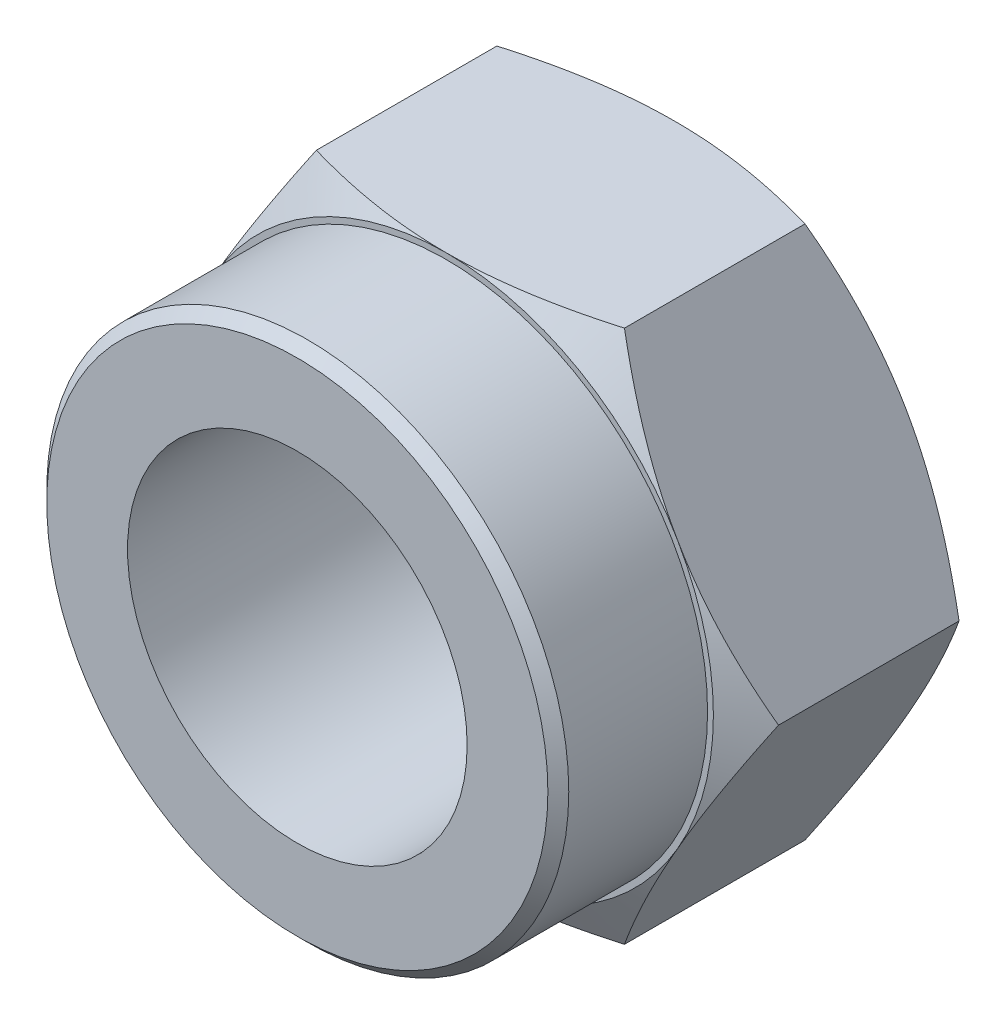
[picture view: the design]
ISO-10303-21;
HEADER;
FILE_DESCRIPTION(('STEP AP214'),'2;1');
FILE_NAME('part.step','',(''),(''),'','','');
FILE_SCHEMA(('AUTOMOTIVE_DESIGN { 1 0 10303 214 1 1 1 1 }'));
ENDSEC;
DATA;
#1=APPLICATION_CONTEXT('core data for automotive mechanical design processes');
#2=APPLICATION_PROTOCOL_DEFINITION('international standard','automotive_design',2000,#1);
#3=PRODUCT_CONTEXT('',#1,'mechanical');
#4=PRODUCT('Part','Part','',(#3));
#5=PRODUCT_RELATED_PRODUCT_CATEGORY('part','',(#4));
#6=PRODUCT_DEFINITION_FORMATION('','',#4);
#7=PRODUCT_DEFINITION_CONTEXT('part definition',#1,'design');
#8=PRODUCT_DEFINITION('design','',#6,#7);
#9=PRODUCT_DEFINITION_SHAPE('','',#8);
#10=(LENGTH_UNIT() NAMED_UNIT(*) SI_UNIT(.MILLI.,.METRE.));
#11=(NAMED_UNIT(*) PLANE_ANGLE_UNIT() SI_UNIT($,.RADIAN.));
#12=(NAMED_UNIT(*) SI_UNIT($,.STERADIAN.) SOLID_ANGLE_UNIT());
#13=UNCERTAINTY_MEASURE_WITH_UNIT(LENGTH_MEASURE(1.E-05),#10,'distance_accuracy_value','');
#14=(GEOMETRIC_REPRESENTATION_CONTEXT(3) GLOBAL_UNCERTAINTY_ASSIGNED_CONTEXT((#13)) GLOBAL_UNIT_ASSIGNED_CONTEXT((#10,
#11,#12)) REPRESENTATION_CONTEXT('',''));
#15=CARTESIAN_POINT('',(0.,0.,0.));
#16=DIRECTION('',(0.,0.,1.));
#17=DIRECTION('',(1.,0.,0.));
#18=AXIS2_PLACEMENT_3D('',#15,#16,#17);
#19=CARTESIAN_POINT('',(47.6313972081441,-27.5,-23.52));
#20=DIRECTION('',(0.,0.,1.));
#21=DIRECTION('',(1.,0.,0.));
#22=AXIS2_PLACEMENT_3D('',#19,#20,#21);
#23=PLANE('',#22);
#24=CARTESIAN_POINT('',(0.,0.,-23.52));
#25=DIRECTION('',(0.,0.,1.));
#26=DIRECTION('',(1.,0.,0.));
#27=AXIS2_PLACEMENT_3D('',#24,#25,#26);
#28=CIRCLE('',#27,27.5);
#29=CARTESIAN_POINT('',(23.8156986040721,13.75,-23.52));
#30=VERTEX_POINT('',#29);
#31=CARTESIAN_POINT('',(0.,27.5,-23.52));
#32=VERTEX_POINT('',#31);
#33=EDGE_CURVE('E303',#30,#32,#28,.T.);
#34=ORIENTED_EDGE('',*,*,#33,.F.);
#35=CARTESIAN_POINT('',(23.8156986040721,-13.75,-23.52));
#36=VERTEX_POINT('',#35);
#37=EDGE_CURVE('E299',#36,#30,#28,.T.);
#38=ORIENTED_EDGE('',*,*,#37,.F.);
#39=CARTESIAN_POINT('',(0.,-27.5,-23.52));
#40=VERTEX_POINT('',#39);
#41=EDGE_CURVE('E301',#40,#36,#28,.T.);
#42=ORIENTED_EDGE('',*,*,#41,.F.);
#43=CARTESIAN_POINT('',(-23.8156986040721,-13.75,-23.52));
#44=VERTEX_POINT('',#43);
#45=EDGE_CURVE('E387',#44,#40,#28,.T.);
#46=ORIENTED_EDGE('',*,*,#45,.F.);
#47=CARTESIAN_POINT('',(-23.8156986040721,13.75,-23.52));
#48=VERTEX_POINT('',#47);
#49=EDGE_CURVE('E388',#48,#44,#28,.T.);
#50=ORIENTED_EDGE('',*,*,#49,.F.);
#51=CARTESIAN_POINT('',(0.,0.,-23.52));
#52=DIRECTION('',(0.,0.,-1.));
#53=DIRECTION('',(-1.,0.,0.));
#54=AXIS2_PLACEMENT_3D('',#51,#52,#53);
#55=CIRCLE('',#54,27.5);
#56=EDGE_CURVE('E272',#48,#32,#55,.T.);
#57=ORIENTED_EDGE('',*,*,#56,.T.);
#58=EDGE_LOOP('',(#34,#38,#42,#46,#50,#57));
#59=FACE_BOUND('',#58,.T.);
#60=CARTESIAN_POINT('',(0.,0.,-23.52));
#61=DIRECTION('',(0.,0.,-1.));
#62=DIRECTION('',(-1.,0.,0.));
#63=AXIS2_PLACEMENT_3D('',#60,#61,#62);
#64=CIRCLE('',#63,19.45);
#65=CARTESIAN_POINT('',(-19.45,0.,-23.52));
#66=VERTEX_POINT('',#65);
#67=EDGE_CURVE('E558',#66,#66,#64,.T.);
#68=ORIENTED_EDGE('',*,*,#67,.F.);
#69=EDGE_LOOP('',(#68));
#70=FACE_BOUND('',#69,.T.);
#71=ADVANCED_FACE('F37',(#59,#70),#23,.F.);
#72=CARTESIAN_POINT('',(0.,0.,-23.52));
#73=DIRECTION('',(0.,0.,1.));
#74=DIRECTION('',(1.,0.,0.));
#75=AXIS2_PLACEMENT_3D('',#72,#73,#74);
#76=CYLINDRICAL_SURFACE('',#75,17.5);
#77=CARTESIAN_POINT('',(0.,0.,15.38));
#78=DIRECTION('',(0.,0.,1.));
#79=DIRECTION('',(1.,0.,0.));
#80=AXIS2_PLACEMENT_3D('',#77,#78,#79);
#81=CIRCLE('',#80,17.5);
#82=CARTESIAN_POINT('',(17.5,0.,15.38));
#83=VERTEX_POINT('',#82);
#84=EDGE_CURVE('E555',#83,#83,#81,.T.);
#85=ORIENTED_EDGE('',*,*,#84,.T.);
#86=EDGE_LOOP('',(#85));
#87=FACE_BOUND('',#86,.T.);
#88=CARTESIAN_POINT('',(0.,0.,-22.3941669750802));
#89=DIRECTION('',(0.,0.,-1.));
#90=DIRECTION('',(-1.,0.,0.));
#91=AXIS2_PLACEMENT_3D('',#88,#89,#90);
#92=CIRCLE('',#91,17.5);
#93=CARTESIAN_POINT('',(-17.5,0.,-22.3941669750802));
#94=VERTEX_POINT('',#93);
#95=EDGE_CURVE('E563',#94,#94,#92,.T.);
#96=ORIENTED_EDGE('',*,*,#95,.T.);
#97=EDGE_LOOP('',(#96));
#98=FACE_BOUND('',#97,.T.);
#99=ADVANCED_FACE('F322',(#87,#98),#76,.F.);
#100=CARTESIAN_POINT('',(47.6313972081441,-27.5,0.));
#101=DIRECTION('',(0.,0.,1.));
#102=DIRECTION('',(1.,0.,0.));
#103=AXIS2_PLACEMENT_3D('',#100,#101,#102);
#104=PLANE('',#103);
#105=CARTESIAN_POINT('',(0.,0.,0.));
#106=DIRECTION('',(0.,0.,1.));
#107=DIRECTION('',(1.,0.,0.));
#108=AXIS2_PLACEMENT_3D('',#105,#106,#107);
#109=CIRCLE('',#108,27.5);
#110=CARTESIAN_POINT('',(23.8156986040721,-13.75,0.));
#111=VERTEX_POINT('',#110);
#112=CARTESIAN_POINT('',(23.8156986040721,13.75,0.));
#113=VERTEX_POINT('',#112);
#114=EDGE_CURVE('E304',#111,#113,#109,.T.);
#115=ORIENTED_EDGE('',*,*,#114,.T.);
#116=CARTESIAN_POINT('',(0.,27.5,0.));
#117=VERTEX_POINT('',#116);
#118=EDGE_CURVE('E52',#113,#117,#109,.T.);
#119=ORIENTED_EDGE('',*,*,#118,.T.);
#120=CARTESIAN_POINT('',(0.,0.,0.));
#121=DIRECTION('',(0.,0.,-1.));
#122=DIRECTION('',(-1.,0.,0.));
#123=AXIS2_PLACEMENT_3D('',#120,#121,#122);
#124=CIRCLE('',#123,27.5);
#125=CARTESIAN_POINT('',(-23.8156986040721,13.75,0.));
#126=VERTEX_POINT('',#125);
#127=EDGE_CURVE('E131',#126,#117,#124,.T.);
#128=ORIENTED_EDGE('',*,*,#127,.F.);
#129=CARTESIAN_POINT('',(-23.8156986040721,-13.75,0.));
#130=VERTEX_POINT('',#129);
#131=EDGE_CURVE('E142',#126,#130,#109,.T.);
#132=ORIENTED_EDGE('',*,*,#131,.T.);
#133=CARTESIAN_POINT('',(0.,-27.5,0.));
#134=VERTEX_POINT('',#133);
#135=EDGE_CURVE('E150',#130,#134,#109,.T.);
#136=ORIENTED_EDGE('',*,*,#135,.T.);
#137=EDGE_CURVE('E305',#134,#111,#109,.T.);
#138=ORIENTED_EDGE('',*,*,#137,.T.);
#139=EDGE_LOOP('',(#115,#119,#128,#132,#136,#138));
#140=FACE_BOUND('',#139,.T.);
#141=CARTESIAN_POINT('',(0.,0.,5.6843418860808E-11));
#142=DIRECTION('',(0.,0.,1.));
#143=DIRECTION('',(1.,0.,0.));
#144=AXIS2_PLACEMENT_3D('',#141,#142,#143);
#145=CIRCLE('',#144,26.9);
#146=CARTESIAN_POINT('',(26.9,0.,5.6843418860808E-11));
#147=VERTEX_POINT('',#146);
#148=EDGE_CURVE('E156',#147,#147,#145,.T.);
#149=ORIENTED_EDGE('',*,*,#148,.F.);
#150=EDGE_LOOP('',(#149));
#151=FACE_BOUND('',#150,.T.);
#152=ADVANCED_FACE('F153',(#140,#151),#104,.T.);
#153=CARTESIAN_POINT('',(-15.8771324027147,-27.5,-23.52));
#154=DIRECTION('',(0.,-1.,0.));
#155=DIRECTION('',(1.,0.,0.));
#156=AXIS2_PLACEMENT_3D('',#153,#154,#155);
#157=PLANE('',#156);
#158=DIRECTION('',(0.,0.,1.));
#159=VECTOR('',#158,1.);
#160=CARTESIAN_POINT('',(15.8771324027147,-27.5,-23.52));
#161=LINE('',#160,#159);
#162=CARTESIAN_POINT('',(15.8771324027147,-27.5,-21.0637990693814));
#163=VERTEX_POINT('',#162);
#164=CARTESIAN_POINT('',(15.8771324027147,-27.5,-2.45620093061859));
#165=VERTEX_POINT('',#164);
#166=EDGE_CURVE('E284',#163,#165,#161,.T.);
#167=ORIENTED_EDGE('',*,*,#166,.T.);
#168=CARTESIAN_POINT('',(-42.108494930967,-27.5,-13.1594843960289));
#169=CARTESIAN_POINT('',(-41.5048149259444,-27.5,-12.8676772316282));
#170=CARTESIAN_POINT('',(-40.9004047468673,-27.5,-12.5773758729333));
#171=CARTESIAN_POINT('',(-39.6899708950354,-27.5,-12.0001403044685));
#172=CARTESIAN_POINT('',(-39.0839472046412,-27.5,-11.7132061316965));
#173=CARTESIAN_POINT('',(-37.8700434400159,-27.5,-11.1430185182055));
#174=CARTESIAN_POINT('',(-37.2621630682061,-27.5,-10.8597657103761));
#175=CARTESIAN_POINT('',(-36.0444843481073,-27.5,-10.2974192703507));
#176=CARTESIAN_POINT('',(-35.4346860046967,-27.5,-10.0183256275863));
#177=CARTESIAN_POINT('',(-33.5951504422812,-27.5,-9.18481184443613));
#178=CARTESIAN_POINT('',(-32.3622101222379,-27.5,-8.6374301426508));
#179=CARTESIAN_POINT('',(-29.8861914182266,-27.5,-7.56614589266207));
#180=CARTESIAN_POINT('',(-28.6431135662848,-27.5,-7.04224212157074));
#181=CARTESIAN_POINT('',(-26.761690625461,-27.5,-6.27565669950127));
#182=CARTESIAN_POINT('',(-26.1278670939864,-27.5,-6.02186622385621));
#183=CARTESIAN_POINT('',(-24.856813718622,-27.5,-5.52297472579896));
#184=CARTESIAN_POINT('',(-24.2195839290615,-27.5,-5.27787356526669));
#185=CARTESIAN_POINT('',(-22.9413245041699,-27.5,-4.79748145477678));
#186=CARTESIAN_POINT('',(-22.3002943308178,-27.5,-4.56219193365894));
#187=CARTESIAN_POINT('',(-21.0142476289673,-27.5,-4.10280247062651));
#188=CARTESIAN_POINT('',(-20.3692311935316,-27.5,-3.87870226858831));
#189=CARTESIAN_POINT('',(-19.0762913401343,-27.5,-3.44366382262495));
#190=CARTESIAN_POINT('',(-18.4283771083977,-27.5,-3.23269841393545));
#191=CARTESIAN_POINT('',(-17.1280636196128,-27.5,-2.82511808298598));
#192=CARTESIAN_POINT('',(-16.4756642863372,-27.5,-2.6285034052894));
#193=CARTESIAN_POINT('',(-14.5117448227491,-27.5,-2.06306953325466));
#194=CARTESIAN_POINT('',(-13.1930050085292,-27.5,-1.71848993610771));
#195=CARTESIAN_POINT('',(-11.2007577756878,-27.5,-1.26283436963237));
#196=CARTESIAN_POINT('',(-10.5341776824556,-27.5,-1.12112816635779));
#197=CARTESIAN_POINT('',(-9.19657522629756,-27.5,-0.8603576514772));
#198=CARTESIAN_POINT('',(-8.52555296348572,-27.5,-0.741292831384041));
#199=CARTESIAN_POINT('',(-7.17952384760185,-27.5,-0.527916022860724));
#200=CARTESIAN_POINT('',(-6.50451675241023,-27.5,-0.4336055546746));
#201=CARTESIAN_POINT('',(-5.15128946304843,-27.5,-0.271631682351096));
#202=CARTESIAN_POINT('',(-4.47306926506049,-27.5,-0.203968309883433));
#203=CARTESIAN_POINT('',(-3.11871087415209,-27.5,-0.0971102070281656));
#204=CARTESIAN_POINT('',(-2.44258682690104,-27.5,-0.0577373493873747));
#205=CARTESIAN_POINT('',(-1.08928096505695,-27.5,-0.00766728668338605));
#206=CARTESIAN_POINT('',(-0.412099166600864,-27.5,0.00303035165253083));
#207=CARTESIAN_POINT('',(0.941918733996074,-27.5,-0.00450365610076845));
#208=CARTESIAN_POINT('',(1.61875487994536,-27.5,-0.0227272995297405));
#209=CARTESIAN_POINT('',(2.97106504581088,-27.5,-0.0876510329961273));
#210=CARTESIAN_POINT('',(3.64653900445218,-27.5,-0.134352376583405));
#211=CARTESIAN_POINT('',(5.28317631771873,-27.5,-0.281033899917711));
#212=CARTESIAN_POINT('',(6.24308439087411,-27.5,-0.395253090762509));
#213=CARTESIAN_POINT('',(8.15543073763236,-27.5,-0.674849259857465));
#214=CARTESIAN_POINT('',(9.10786788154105,-27.5,-0.840233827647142));
#215=CARTESIAN_POINT('',(11.0057578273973,-27.5,-1.21653474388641));
#216=CARTESIAN_POINT('',(11.9511910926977,-27.5,-1.42754869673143));
#217=CARTESIAN_POINT('',(13.8323781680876,-27.5,-1.88855596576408));
#218=CARTESIAN_POINT('',(14.7681323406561,-27.5,-2.13854781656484));
#219=CARTESIAN_POINT('',(16.6519981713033,-27.5,-2.67777771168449));
#220=CARTESIAN_POINT('',(17.5998839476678,-27.5,-2.96779955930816));
#221=CARTESIAN_POINT('',(19.4863693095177,-27.5,-3.57671795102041));
#222=CARTESIAN_POINT('',(20.4249680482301,-27.5,-3.89561710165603));
#223=CARTESIAN_POINT('',(22.2883658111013,-27.5,-4.55554423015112));
#224=CARTESIAN_POINT('',(23.2132128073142,-27.5,-4.89643727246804));
#225=CARTESIAN_POINT('',(24.594651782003,-27.5,-5.42253409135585));
#226=CARTESIAN_POINT('',(25.0540862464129,-27.5,-5.60032951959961));
#227=CARTESIAN_POINT('',(25.9711665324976,-27.5,-5.96043932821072));
#228=CARTESIAN_POINT('',(26.4288124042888,-27.5,-6.14275358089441));
#229=CARTESIAN_POINT('',(26.8856293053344,-27.5,-6.32712441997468));
#230=B_SPLINE_CURVE_WITH_KNOTS('',3,(#168,#169,#170,#171,#172,#173,#174,#175,#176,#177,#178,
#179,#180,#181,#182,#183,#184,#185,#186,#187,#188,#189,#190,#191,#192,#193,#194,#195,#196,#197,
#198,#199,#200,#201,#202,#203,#204,#205,#206,#207,#208,#209,#210,#211,#212,#213,#214,#215,#216,
#217,#218,#219,#220,#221,#222,#223,#224,#225,#226,#227,#228,#229),.UNSPECIFIED.,.F.,.F.,(4,2,2,
2,2,2,2,2,2,2,2,2,2,2,2,2,2,2,2,2,2,2,2,2,2,2,2,2,2,2,4),(0.,2.01152483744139,4.02307175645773,
6.034960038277,8.0468432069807,12.0936174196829,16.1401806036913,18.1883662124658,
20.2365192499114,22.2849695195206,24.3333721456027,26.3773870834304,28.42143684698,
32.5079579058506,34.5520769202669,36.5961500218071,38.640348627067,40.6845496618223,
42.7157641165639,44.7469478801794,46.7775697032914,48.808280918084,51.7067063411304,
54.6055619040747,57.510680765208,60.4156904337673,63.3889230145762,66.3624242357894,
69.3191566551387,70.7970485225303,72.2748986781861),.UNSPECIFIED.);
#231=EDGE_CURVE('E60',#165,#134,#230,.F.);
#232=ORIENTED_EDGE('',*,*,#231,.T.);
#233=CARTESIAN_POINT('',(-15.8771324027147,-27.5,-2.45620093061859));
#234=VERTEX_POINT('',#233);
#235=EDGE_CURVE('E266',#134,#234,#230,.F.);
#236=ORIENTED_EDGE('',*,*,#235,.T.);
#237=DIRECTION('',(0.,0.,1.));
#238=VECTOR('',#237,1.);
#239=CARTESIAN_POINT('',(-15.8771324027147,-27.5,-23.52));
#240=LINE('',#239,#238);
#241=CARTESIAN_POINT('',(-15.8771324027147,-27.5,-21.0637990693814));
#242=VERTEX_POINT('',#241);
#243=EDGE_CURVE('E302',#242,#234,#240,.T.);
#244=ORIENTED_EDGE('',*,*,#243,.F.);
#245=CARTESIAN_POINT('',(-42.108494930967,-27.5,-10.3605156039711));
#246=CARTESIAN_POINT('',(-41.5048149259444,-27.5,-10.6523227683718));
#247=CARTESIAN_POINT('',(-40.9004047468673,-27.5,-10.9426241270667));
#248=CARTESIAN_POINT('',(-39.6899708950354,-27.5,-11.5198596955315));
#249=CARTESIAN_POINT('',(-39.0839472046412,-27.5,-11.8067938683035));
#250=CARTESIAN_POINT('',(-37.8700434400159,-27.5,-12.3769814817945));
#251=CARTESIAN_POINT('',(-37.2621630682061,-27.5,-12.660234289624));
#252=CARTESIAN_POINT('',(-36.0444843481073,-27.5,-13.2225807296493));
#253=CARTESIAN_POINT('',(-35.4346860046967,-27.5,-13.5016743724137));
#254=CARTESIAN_POINT('',(-33.5951504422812,-27.5,-14.3351881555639));
#255=CARTESIAN_POINT('',(-32.3622101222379,-27.5,-14.8825698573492));
#256=CARTESIAN_POINT('',(-29.8861914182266,-27.5,-15.9538541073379));
#257=CARTESIAN_POINT('',(-28.6431135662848,-27.5,-16.4777578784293));
#258=CARTESIAN_POINT('',(-26.761690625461,-27.5,-17.2443433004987));
#259=CARTESIAN_POINT('',(-26.1278670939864,-27.5,-17.4981337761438));
#260=CARTESIAN_POINT('',(-24.856813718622,-27.5,-17.997025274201));
#261=CARTESIAN_POINT('',(-24.2195839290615,-27.5,-18.2421264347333));
#262=CARTESIAN_POINT('',(-22.9413245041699,-27.5,-18.7225185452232));
#263=CARTESIAN_POINT('',(-22.3002943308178,-27.5,-18.9578080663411));
#264=CARTESIAN_POINT('',(-21.0142476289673,-27.5,-19.4171975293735));
#265=CARTESIAN_POINT('',(-20.3692311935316,-27.5,-19.6412977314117));
#266=CARTESIAN_POINT('',(-19.0762913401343,-27.5,-20.076336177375));
#267=CARTESIAN_POINT('',(-18.4283771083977,-27.5,-20.2873015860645));
#268=CARTESIAN_POINT('',(-17.1280636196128,-27.5,-20.694881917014));
#269=CARTESIAN_POINT('',(-16.4756642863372,-27.5,-20.8914965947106));
#270=CARTESIAN_POINT('',(-14.5117448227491,-27.5,-21.4569304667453));
#271=CARTESIAN_POINT('',(-13.1930050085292,-27.5,-21.8015100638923));
#272=CARTESIAN_POINT('',(-11.2007577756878,-27.5,-22.2571656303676));
#273=CARTESIAN_POINT('',(-10.5341776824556,-27.5,-22.3988718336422));
#274=CARTESIAN_POINT('',(-9.19657522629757,-27.5,-22.6596423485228));
#275=CARTESIAN_POINT('',(-8.52555296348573,-27.5,-22.778707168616));
#276=CARTESIAN_POINT('',(-7.17952384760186,-27.5,-22.9920839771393));
#277=CARTESIAN_POINT('',(-6.50451675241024,-27.5,-23.0863944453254));
#278=CARTESIAN_POINT('',(-5.15128946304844,-27.5,-23.2483683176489));
#279=CARTESIAN_POINT('',(-4.4730692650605,-27.5,-23.3160316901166));
#280=CARTESIAN_POINT('',(-3.1187108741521,-27.5,-23.4228897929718));
#281=CARTESIAN_POINT('',(-2.44258682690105,-27.5,-23.4622626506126));
#282=CARTESIAN_POINT('',(-1.08928096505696,-27.5,-23.5123327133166));
#283=CARTESIAN_POINT('',(-0.412099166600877,-27.5,-23.5230303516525));
#284=CARTESIAN_POINT('',(0.941918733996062,-27.5,-23.5154963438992));
#285=CARTESIAN_POINT('',(1.61875487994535,-27.5,-23.4972727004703));
#286=CARTESIAN_POINT('',(2.97106504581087,-27.5,-23.4323489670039));
#287=CARTESIAN_POINT('',(3.64653900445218,-27.5,-23.3856476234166));
#288=CARTESIAN_POINT('',(5.28317631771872,-27.5,-23.2389661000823));
#289=CARTESIAN_POINT('',(6.24308439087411,-27.5,-23.1247469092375));
#290=CARTESIAN_POINT('',(8.15543073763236,-27.5,-22.8451507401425));
#291=CARTESIAN_POINT('',(9.10786788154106,-27.5,-22.6797661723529));
#292=CARTESIAN_POINT('',(11.0057578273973,-27.5,-22.3034652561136));
#293=CARTESIAN_POINT('',(11.9511910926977,-27.5,-22.0924513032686));
#294=CARTESIAN_POINT('',(13.8323781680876,-27.5,-21.6314440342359));
#295=CARTESIAN_POINT('',(14.7681323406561,-27.5,-21.3814521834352));
#296=CARTESIAN_POINT('',(16.6519981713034,-27.5,-20.8422222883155));
#297=CARTESIAN_POINT('',(17.5998839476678,-27.5,-20.5522004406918));
#298=CARTESIAN_POINT('',(19.4863693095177,-27.5,-19.9432820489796));
#299=CARTESIAN_POINT('',(20.4249680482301,-27.5,-19.624382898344));
#300=CARTESIAN_POINT('',(22.2883658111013,-27.5,-18.9644557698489));
#301=CARTESIAN_POINT('',(23.2132128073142,-27.5,-18.623562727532));
#302=CARTESIAN_POINT('',(24.594651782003,-27.5,-18.0974659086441));
#303=CARTESIAN_POINT('',(25.0540862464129,-27.5,-17.9196704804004));
#304=CARTESIAN_POINT('',(25.9711665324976,-27.5,-17.5595606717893));
#305=CARTESIAN_POINT('',(26.4288124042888,-27.5,-17.3772464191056));
#306=CARTESIAN_POINT('',(26.8856293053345,-27.5,-17.1928755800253));
#307=B_SPLINE_CURVE_WITH_KNOTS('',3,(#245,#246,#247,#248,#249,#250,#251,#252,#253,#254,#255,
#256,#257,#258,#259,#260,#261,#262,#263,#264,#265,#266,#267,#268,#269,#270,#271,#272,#273,#274,
#275,#276,#277,#278,#279,#280,#281,#282,#283,#284,#285,#286,#287,#288,#289,#290,#291,#292,#293,
#294,#295,#296,#297,#298,#299,#300,#301,#302,#303,#304,#305,#306),.UNSPECIFIED.,.F.,.F.,(4,2,2,
2,2,2,2,2,2,2,2,2,2,2,2,2,2,2,2,2,2,2,2,2,2,2,2,2,2,2,4),(0.,2.01152483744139,4.02307175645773,
6.034960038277,8.04684320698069,12.0936174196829,16.1401806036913,18.1883662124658,
20.2365192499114,22.2849695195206,24.3333721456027,26.3773870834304,28.42143684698,
32.5079579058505,34.5520769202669,36.596150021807,38.640348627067,40.6845496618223,
42.7157641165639,44.7469478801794,46.7775697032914,48.808280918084,51.7067063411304,
54.6055619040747,57.5106807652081,60.4156904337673,63.3889230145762,66.3624242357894,
69.3191566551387,70.7970485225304,72.2748986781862),.UNSPECIFIED.);
#308=EDGE_CURVE('E253',#242,#40,#307,.T.);
#309=ORIENTED_EDGE('',*,*,#308,.T.);
#310=EDGE_CURVE('E238',#40,#163,#307,.T.);
#311=ORIENTED_EDGE('',*,*,#310,.T.);
#312=EDGE_LOOP('',(#167,#232,#236,#244,#309,#311));
#313=FACE_BOUND('',#312,.T.);
#314=ADVANCED_FACE('F260',(#313),#157,.T.);
#315=CARTESIAN_POINT('',(-31.7542648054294,0.,-23.52));
#316=DIRECTION('',(-0.866025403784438,-0.5,0.));
#317=DIRECTION('',(0.5,-0.866025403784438,0.));
#318=AXIS2_PLACEMENT_3D('',#315,#316,#317);
#319=PLANE('',#318);
#320=ORIENTED_EDGE('',*,*,#243,.T.);
#321=CARTESIAN_POINT('',(-15.8770169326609,-27.5002,-2.45626759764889));
#322=CARTESIAN_POINT('',(-16.2259892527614,-26.8957622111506,-2.25480335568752));
#323=CARTESIAN_POINT('',(-16.5763227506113,-26.2889667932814,-2.06248134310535));
#324=CARTESIAN_POINT('',(-17.2797989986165,-25.0705101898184,-1.69866297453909));
#325=CARTESIAN_POINT('',(-17.6329426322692,-24.4588474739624,-1.52717346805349));
#326=CARTESIAN_POINT('',(-18.3427291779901,-23.229461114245,-1.20732190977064));
#327=CARTESIAN_POINT('',(-18.6993783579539,-22.6117266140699,-1.05901508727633));
#328=CARTESIAN_POINT('',(-19.4151397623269,-21.371991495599,-0.78872376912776));
#329=CARTESIAN_POINT('',(-19.7742517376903,-20.7499913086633,-0.666736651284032));
#330=CARTESIAN_POINT('',(-20.4857595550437,-19.5176236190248,-0.454262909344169));
#331=CARTESIAN_POINT('',(-20.8381026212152,-18.907347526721,-0.363073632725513));
#332=CARTESIAN_POINT('',(-21.5444032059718,-17.683999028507,-0.210170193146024));
#333=CARTESIAN_POINT('',(-21.8983607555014,-17.0709265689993,-0.148456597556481));
#334=CARTESIAN_POINT('',(-22.6068704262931,-15.8437518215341,-0.056062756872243));
#335=CARTESIAN_POINT('',(-22.9614213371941,-15.2296516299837,-0.025345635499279));
#336=CARTESIAN_POINT('',(-23.6708503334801,-14.0008845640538,0.0043946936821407));
#337=CARTESIAN_POINT('',(-24.025728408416,-13.3862177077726,0.00341888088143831));
#338=CARTESIAN_POINT('',(-24.6891773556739,-12.2370904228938,-0.028012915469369));
#339=CARTESIAN_POINT('',(-24.9977954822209,-11.7025481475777,-0.054636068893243));
#340=CARTESIAN_POINT('',(-25.6142949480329,-10.6347397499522,-0.131346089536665));
#341=CARTESIAN_POINT('',(-25.9221762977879,-10.1014736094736,-0.18143262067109));
#342=CARTESIAN_POINT('',(-26.5370884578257,-9.03641450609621,-0.304201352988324));
#343=CARTESIAN_POINT('',(-26.8441182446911,-8.50462331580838,-0.376903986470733));
#344=CARTESIAN_POINT('',(-27.4567077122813,-7.44358723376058,-0.54361822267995));
#345=CARTESIAN_POINT('',(-27.7622673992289,-6.9143423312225,-0.637629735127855));
#346=CARTESIAN_POINT('',(-28.6898814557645,-5.3076676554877,-0.954040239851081));
#347=CARTESIAN_POINT('',(-29.3093003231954,-4.23480270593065,-1.20800596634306));
#348=CARTESIAN_POINT('',(-30.2315881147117,-2.63735339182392,-1.64037055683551));
#349=CARTESIAN_POINT('',(-30.5376130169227,-2.10730271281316,-1.79290583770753));
#350=CARTESIAN_POINT('',(-31.1475461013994,-1.05086762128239,-2.11341869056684));
#351=CARTESIAN_POINT('',(-31.4514548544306,-0.524482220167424,-2.28139191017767));
#352=CARTESIAN_POINT('',(-31.7543802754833,0.000199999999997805,-2.4562675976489));
#353=B_SPLINE_CURVE_WITH_KNOTS('',3,(#321,#322,#323,#324,#325,#326,#327,#328,#329,#330,#331,
#332,#333,#334,#335,#336,#337,#338,#339,#340,#341,#342,#343,#344,#345,#346,#347,#348,#349,#350,
#351,#352),.UNSPECIFIED.,.F.,.F.,(4,2,2,2,2,2,2,2,2,2,2,2,2,2,2,4),(0.,2.17937596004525,
4.35946654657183,6.54467421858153,8.72966408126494,10.8607692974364,12.9919155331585,
15.120523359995,17.2490654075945,19.1020483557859,20.9550047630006,22.8096400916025,
24.6642675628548,28.4552152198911,30.3473870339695,32.2390270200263),.UNSPECIFIED.);
#354=EDGE_CURVE('E163',#234,#130,#353,.T.);
#355=ORIENTED_EDGE('',*,*,#354,.T.);
#356=CARTESIAN_POINT('',(-31.7542648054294,0.,-2.45620093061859));
#357=VERTEX_POINT('',#356);
#358=EDGE_CURVE('E145',#130,#357,#353,.T.);
#359=ORIENTED_EDGE('',*,*,#358,.T.);
#360=DIRECTION('',(0.,0.,1.));
#361=VECTOR('',#360,1.);
#362=CARTESIAN_POINT('',(-31.7542648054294,0.,-23.52));
#363=LINE('',#362,#361);
#364=CARTESIAN_POINT('',(-31.7542648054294,0.,-21.0637990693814));
#365=VERTEX_POINT('',#364);
#366=EDGE_CURVE('E162',#365,#357,#363,.T.);
#367=ORIENTED_EDGE('',*,*,#366,.F.);
#368=CARTESIAN_POINT('',(-31.7543802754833,0.000199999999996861,-21.0637324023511));
#369=CARTESIAN_POINT('',(-31.4054079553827,-0.60423778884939,-21.2651966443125));
#370=CARTESIAN_POINT('',(-31.0550744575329,-1.21103320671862,-21.4575186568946));
#371=CARTESIAN_POINT('',(-30.3515982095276,-2.42948981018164,-21.8213370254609));
#372=CARTESIAN_POINT('',(-29.9984545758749,-3.04115252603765,-21.9928265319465));
#373=CARTESIAN_POINT('',(-29.288668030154,-4.27053888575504,-22.3126780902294));
#374=CARTESIAN_POINT('',(-28.9320188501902,-4.88827338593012,-22.4609849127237));
#375=CARTESIAN_POINT('',(-28.2162574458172,-6.12800850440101,-22.7312762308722));
#376=CARTESIAN_POINT('',(-27.8571454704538,-6.75000869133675,-22.853263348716));
#377=CARTESIAN_POINT('',(-27.1456376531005,-7.98237638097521,-23.0657370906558));
#378=CARTESIAN_POINT('',(-26.7932945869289,-8.59265247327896,-23.1569263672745));
#379=CARTESIAN_POINT('',(-26.0869940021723,-9.81600097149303,-23.309829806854));
#380=CARTESIAN_POINT('',(-25.7330364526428,-10.4290734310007,-23.3715434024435));
#381=CARTESIAN_POINT('',(-25.024526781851,-11.6562481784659,-23.4639372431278));
#382=CARTESIAN_POINT('',(-24.66997587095,-12.2703483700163,-23.4946543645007));
#383=CARTESIAN_POINT('',(-23.960546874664,-13.4991154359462,-23.5243946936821));
#384=CARTESIAN_POINT('',(-23.6056687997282,-14.1137822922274,-23.5234188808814));
#385=CARTESIAN_POINT('',(-22.9422198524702,-15.2629095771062,-23.4919870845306));
#386=CARTESIAN_POINT('',(-22.6336017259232,-15.7974518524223,-23.4653639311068));
#387=CARTESIAN_POINT('',(-22.0171022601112,-16.8652602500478,-23.3886539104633));
#388=CARTESIAN_POINT('',(-21.7092209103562,-17.3985263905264,-23.3385673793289));
#389=CARTESIAN_POINT('',(-21.0943087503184,-18.4635854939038,-23.2157986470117));
#390=CARTESIAN_POINT('',(-20.787278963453,-18.9953766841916,-23.1430960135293));
#391=CARTESIAN_POINT('',(-20.1746894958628,-20.0564127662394,-22.9763817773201));
#392=CARTESIAN_POINT('',(-19.8691298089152,-20.5856576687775,-22.8823702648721));
#393=CARTESIAN_POINT('',(-18.9415157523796,-22.1923323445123,-22.5659597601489));
#394=CARTESIAN_POINT('',(-18.3220968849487,-23.2651972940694,-22.3119940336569));
#395=CARTESIAN_POINT('',(-17.3998090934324,-24.8626466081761,-21.8796294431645));
#396=CARTESIAN_POINT('',(-17.0937841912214,-25.3926972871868,-21.7270941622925));
#397=CARTESIAN_POINT('',(-16.4838511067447,-26.4491323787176,-21.4065813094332));
#398=CARTESIAN_POINT('',(-16.1799423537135,-26.9755177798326,-21.2386080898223));
#399=CARTESIAN_POINT('',(-15.8770169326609,-27.5002,-21.0637324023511));
#400=B_SPLINE_CURVE_WITH_KNOTS('',3,(#368,#369,#370,#371,#372,#373,#374,#375,#376,#377,#378,
#379,#380,#381,#382,#383,#384,#385,#386,#387,#388,#389,#390,#391,#392,#393,#394,#395,#396,#397,
#398,#399),.UNSPECIFIED.,.F.,.F.,(4,2,2,2,2,2,2,2,2,2,2,2,2,2,2,4),(0.,2.17937596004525,
4.35946654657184,6.54467421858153,8.72966408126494,10.8607692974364,12.9919155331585,
15.120523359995,17.2490654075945,19.1020483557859,20.9550047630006,22.8096400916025,
24.6642675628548,28.4552152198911,30.3473870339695,32.2390270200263),.UNSPECIFIED.);
#401=EDGE_CURVE('E341',#365,#44,#400,.T.);
#402=ORIENTED_EDGE('',*,*,#401,.T.);
#403=EDGE_CURVE('E335',#44,#242,#400,.T.);
#404=ORIENTED_EDGE('',*,*,#403,.T.);
#405=EDGE_LOOP('',(#320,#355,#359,#367,#402,#404));
#406=FACE_BOUND('',#405,.T.);
#407=ADVANCED_FACE('F263',(#406),#319,.T.);
#408=CARTESIAN_POINT('',(-15.8771324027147,27.5,-23.52));
#409=DIRECTION('',(-0.866025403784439,0.5,0.));
#410=DIRECTION('',(-0.5,-0.866025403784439,0.));
#411=AXIS2_PLACEMENT_3D('',#408,#409,#410);
#412=PLANE('',#411);
#413=ORIENTED_EDGE('',*,*,#366,.T.);
#414=CARTESIAN_POINT('',(-31.7543802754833,-0.000200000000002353,-2.45626759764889));
#415=CARTESIAN_POINT('',(-31.4054079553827,0.604237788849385,-2.25480335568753));
#416=CARTESIAN_POINT('',(-31.0550744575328,1.21103320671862,-2.06248134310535));
#417=CARTESIAN_POINT('',(-30.3515982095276,2.42948981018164,-1.69866297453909));
#418=CARTESIAN_POINT('',(-29.9984545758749,3.04115252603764,-1.52717346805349));
#419=CARTESIAN_POINT('',(-29.288668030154,4.27053888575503,-1.20732190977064));
#420=CARTESIAN_POINT('',(-28.9320188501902,4.88827338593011,-1.05901508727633));
#421=CARTESIAN_POINT('',(-28.2162574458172,6.128008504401,-0.788723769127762));
#422=CARTESIAN_POINT('',(-27.8571454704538,6.75000869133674,-0.666736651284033));
#423=CARTESIAN_POINT('',(-27.1456376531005,7.98237638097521,-0.454262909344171));
#424=CARTESIAN_POINT('',(-26.7932945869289,8.59265247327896,-0.363073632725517));
#425=CARTESIAN_POINT('',(-26.0869940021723,9.81600097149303,-0.210170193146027));
#426=CARTESIAN_POINT('',(-25.7330364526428,10.4290734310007,-0.148456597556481));
#427=CARTESIAN_POINT('',(-25.024526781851,11.6562481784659,-0.0560627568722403));
#428=CARTESIAN_POINT('',(-24.66997587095,12.2703483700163,-0.0253456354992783));
#429=CARTESIAN_POINT('',(-23.960546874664,13.4991154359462,0.00439469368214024));
#430=CARTESIAN_POINT('',(-23.6056687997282,14.1137822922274,0.0034188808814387));
#431=CARTESIAN_POINT('',(-22.9422198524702,15.2629095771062,-0.028012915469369));
#432=CARTESIAN_POINT('',(-22.6336017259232,15.7974518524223,-0.0546360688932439));
#433=CARTESIAN_POINT('',(-22.0171022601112,16.8652602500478,-0.131346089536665));
#434=CARTESIAN_POINT('',(-21.7092209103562,17.3985263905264,-0.181432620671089));
#435=CARTESIAN_POINT('',(-21.0943087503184,18.4635854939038,-0.304201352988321));
#436=CARTESIAN_POINT('',(-20.787278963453,18.9953766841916,-0.376903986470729));
#437=CARTESIAN_POINT('',(-20.1746894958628,20.0564127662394,-0.543618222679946));
#438=CARTESIAN_POINT('',(-19.8691298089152,20.5856576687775,-0.637629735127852));
#439=CARTESIAN_POINT('',(-18.9415157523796,22.1923323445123,-0.954040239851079));
#440=CARTESIAN_POINT('',(-18.3220968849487,23.2651972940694,-1.20800596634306));
#441=CARTESIAN_POINT('',(-17.3998090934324,24.8626466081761,-1.64037055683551));
#442=CARTESIAN_POINT('',(-17.0937841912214,25.3926972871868,-1.79290583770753));
#443=CARTESIAN_POINT('',(-16.4838511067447,26.4491323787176,-2.11341869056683));
#444=CARTESIAN_POINT('',(-16.1799423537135,26.9755177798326,-2.28139191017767));
#445=CARTESIAN_POINT('',(-15.8770169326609,27.5002,-2.45626759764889));
#446=B_SPLINE_CURVE_WITH_KNOTS('',3,(#414,#415,#416,#417,#418,#419,#420,#421,#422,#423,#424,
#425,#426,#427,#428,#429,#430,#431,#432,#433,#434,#435,#436,#437,#438,#439,#440,#441,#442,#443,
#444,#445),.UNSPECIFIED.,.F.,.F.,(4,2,2,2,2,2,2,2,2,2,2,2,2,2,2,4),(0.,2.17937596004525,
4.35946654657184,6.54467421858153,8.72966408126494,10.8607692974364,12.9919155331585,
15.120523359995,17.2490654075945,19.1020483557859,20.9550047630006,22.8096400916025,
24.6642675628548,28.4552152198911,30.3473870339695,32.2390270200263),.UNSPECIFIED.);
#447=EDGE_CURVE('E138',#357,#126,#446,.T.);
#448=ORIENTED_EDGE('',*,*,#447,.T.);
#449=CARTESIAN_POINT('',(-15.8771324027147,27.5,-2.45620093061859));
#450=VERTEX_POINT('',#449);
#451=EDGE_CURVE('E127',#126,#450,#446,.T.);
#452=ORIENTED_EDGE('',*,*,#451,.T.);
#453=DIRECTION('',(0.,0.,1.));
#454=VECTOR('',#453,1.);
#455=CARTESIAN_POINT('',(-15.8771324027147,27.5,-23.52));
#456=LINE('',#455,#454);
#457=CARTESIAN_POINT('',(-15.8771324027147,27.5,-21.0637990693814));
#458=VERTEX_POINT('',#457);
#459=EDGE_CURVE('E350',#458,#450,#456,.T.);
#460=ORIENTED_EDGE('',*,*,#459,.F.);
#461=CARTESIAN_POINT('',(-15.8770169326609,27.5002,-21.0637324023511));
#462=CARTESIAN_POINT('',(-16.2259892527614,26.8957622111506,-21.2651966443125));
#463=CARTESIAN_POINT('',(-16.5763227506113,26.2889667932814,-21.4575186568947));
#464=CARTESIAN_POINT('',(-17.2797989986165,25.0705101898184,-21.8213370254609));
#465=CARTESIAN_POINT('',(-17.6329426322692,24.4588474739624,-21.9928265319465));
#466=CARTESIAN_POINT('',(-18.3427291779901,23.229461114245,-22.3126780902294));
#467=CARTESIAN_POINT('',(-18.6993783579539,22.6117266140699,-22.4609849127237));
#468=CARTESIAN_POINT('',(-19.4151397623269,21.371991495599,-22.7312762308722));
#469=CARTESIAN_POINT('',(-19.7742517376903,20.7499913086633,-22.853263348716));
#470=CARTESIAN_POINT('',(-20.4857595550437,19.5176236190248,-23.0657370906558));
#471=CARTESIAN_POINT('',(-20.8381026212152,18.907347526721,-23.1569263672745));
#472=CARTESIAN_POINT('',(-21.5444032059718,17.683999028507,-23.309829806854));
#473=CARTESIAN_POINT('',(-21.8983607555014,17.0709265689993,-23.3715434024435));
#474=CARTESIAN_POINT('',(-22.6068704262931,15.8437518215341,-23.4639372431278));
#475=CARTESIAN_POINT('',(-22.9614213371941,15.2296516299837,-23.4946543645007));
#476=CARTESIAN_POINT('',(-23.6708503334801,14.0008845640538,-23.5243946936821));
#477=CARTESIAN_POINT('',(-24.025728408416,13.3862177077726,-23.5234188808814));
#478=CARTESIAN_POINT('',(-24.6891773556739,12.2370904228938,-23.4919870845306));
#479=CARTESIAN_POINT('',(-24.9977954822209,11.7025481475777,-23.4653639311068));
#480=CARTESIAN_POINT('',(-25.6142949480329,10.6347397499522,-23.3886539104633));
#481=CARTESIAN_POINT('',(-25.9221762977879,10.1014736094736,-23.3385673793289));
#482=CARTESIAN_POINT('',(-26.5370884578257,9.03641450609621,-23.2157986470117));
#483=CARTESIAN_POINT('',(-26.8441182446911,8.50462331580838,-23.1430960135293));
#484=CARTESIAN_POINT('',(-27.4567077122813,7.44358723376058,-22.9763817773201));
#485=CARTESIAN_POINT('',(-27.7622673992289,6.9143423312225,-22.8823702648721));
#486=CARTESIAN_POINT('',(-28.6898814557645,5.30766765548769,-22.5659597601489));
#487=CARTESIAN_POINT('',(-29.3093003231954,4.23480270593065,-22.3119940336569));
#488=CARTESIAN_POINT('',(-30.2315881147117,2.63735339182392,-21.8796294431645));
#489=CARTESIAN_POINT('',(-30.5376130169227,2.10730271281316,-21.7270941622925));
#490=CARTESIAN_POINT('',(-31.1475461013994,1.05086762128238,-21.4065813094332));
#491=CARTESIAN_POINT('',(-31.4514548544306,0.524482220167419,-21.2386080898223));
#492=CARTESIAN_POINT('',(-31.7543802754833,-0.000200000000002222,-21.0637324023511));
#493=B_SPLINE_CURVE_WITH_KNOTS('',3,(#461,#462,#463,#464,#465,#466,#467,#468,#469,#470,#471,
#472,#473,#474,#475,#476,#477,#478,#479,#480,#481,#482,#483,#484,#485,#486,#487,#488,#489,#490,
#491,#492),.UNSPECIFIED.,.F.,.F.,(4,2,2,2,2,2,2,2,2,2,2,2,2,2,2,4),(0.,2.17937596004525,
4.35946654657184,6.54467421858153,8.72966408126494,10.8607692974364,12.9919155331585,
15.120523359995,17.2490654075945,19.1020483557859,20.9550047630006,22.8096400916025,
24.6642675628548,28.4552152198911,30.3473870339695,32.2390270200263),.UNSPECIFIED.);
#494=EDGE_CURVE('E289',#458,#48,#493,.T.);
#495=ORIENTED_EDGE('',*,*,#494,.T.);
#496=EDGE_CURVE('E295',#48,#365,#493,.T.);
#497=ORIENTED_EDGE('',*,*,#496,.T.);
#498=EDGE_LOOP('',(#413,#448,#452,#460,#495,#497));
#499=FACE_BOUND('',#498,.T.);
#500=ADVANCED_FACE('F159',(#499),#412,.T.);
#501=CARTESIAN_POINT('',(15.8771324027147,27.5,-23.52));
#502=DIRECTION('',(0.,1.,0.));
#503=DIRECTION('',(-1.,0.,0.));
#504=AXIS2_PLACEMENT_3D('',#501,#502,#503);
#505=PLANE('',#504);
#506=ORIENTED_EDGE('',*,*,#459,.T.);
#507=CARTESIAN_POINT('',(-42.108494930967,27.5,-13.1594843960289));
#508=CARTESIAN_POINT('',(-41.5048149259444,27.5,-12.8676772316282));
#509=CARTESIAN_POINT('',(-40.9004047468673,27.5,-12.5773758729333));
#510=CARTESIAN_POINT('',(-39.6899708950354,27.5,-12.0001403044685));
#511=CARTESIAN_POINT('',(-39.0839472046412,27.5,-11.7132061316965));
#512=CARTESIAN_POINT('',(-37.8700434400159,27.5,-11.1430185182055));
#513=CARTESIAN_POINT('',(-37.2621630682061,27.5,-10.8597657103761));
#514=CARTESIAN_POINT('',(-36.0444843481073,27.5,-10.2974192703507));
#515=CARTESIAN_POINT('',(-35.4346860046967,27.5,-10.0183256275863));
#516=CARTESIAN_POINT('',(-33.5951504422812,27.5,-9.18481184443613));
#517=CARTESIAN_POINT('',(-32.3622101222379,27.5,-8.63743014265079));
#518=CARTESIAN_POINT('',(-29.8861914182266,27.5,-7.56614589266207));
#519=CARTESIAN_POINT('',(-28.6431135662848,27.5,-7.04224212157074));
#520=CARTESIAN_POINT('',(-26.761690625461,27.5,-6.27565669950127));
#521=CARTESIAN_POINT('',(-26.1278670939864,27.5,-6.0218662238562));
#522=CARTESIAN_POINT('',(-24.856813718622,27.5,-5.52297472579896));
#523=CARTESIAN_POINT('',(-24.2195839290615,27.5,-5.27787356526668));
#524=CARTESIAN_POINT('',(-22.9413245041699,27.5,-4.79748145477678));
#525=CARTESIAN_POINT('',(-22.3002943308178,27.5,-4.56219193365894));
#526=CARTESIAN_POINT('',(-21.0142476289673,27.5,-4.10280247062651));
#527=CARTESIAN_POINT('',(-20.3692311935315,27.5,-3.87870226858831));
#528=CARTESIAN_POINT('',(-19.0762913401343,27.5,-3.44366382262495));
#529=CARTESIAN_POINT('',(-18.4283771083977,27.5,-3.23269841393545));
#530=CARTESIAN_POINT('',(-17.1280636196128,27.5,-2.82511808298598));
#531=CARTESIAN_POINT('',(-16.4756642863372,27.5,-2.6285034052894));
#532=CARTESIAN_POINT('',(-14.5117448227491,27.5,-2.06306953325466));
#533=CARTESIAN_POINT('',(-13.1930050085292,27.5,-1.71848993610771));
#534=CARTESIAN_POINT('',(-11.2007577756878,27.5,-1.26283436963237));
#535=CARTESIAN_POINT('',(-10.5341776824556,27.5,-1.12112816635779));
#536=CARTESIAN_POINT('',(-9.19657522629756,27.5,-0.860357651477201));
#537=CARTESIAN_POINT('',(-8.52555296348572,27.5,-0.741292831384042));
#538=CARTESIAN_POINT('',(-7.17952384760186,27.5,-0.527916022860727));
#539=CARTESIAN_POINT('',(-6.50451675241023,27.5,-0.433605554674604));
#540=CARTESIAN_POINT('',(-5.15128946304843,27.5,-0.2716316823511));
#541=CARTESIAN_POINT('',(-4.47306926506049,27.5,-0.203968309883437));
#542=CARTESIAN_POINT('',(-3.1187108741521,27.5,-0.0971102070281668));
#543=CARTESIAN_POINT('',(-2.44258682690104,27.5,-0.057737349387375));
#544=CARTESIAN_POINT('',(-1.08928096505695,27.5,-0.00766728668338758));
#545=CARTESIAN_POINT('',(-0.412099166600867,27.5,0.00303035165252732));
#546=CARTESIAN_POINT('',(0.941918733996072,27.5,-0.00450365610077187));
#547=CARTESIAN_POINT('',(1.61875487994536,27.5,-0.0227272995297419));
#548=CARTESIAN_POINT('',(2.97106504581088,27.5,-0.0876510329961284));
#549=CARTESIAN_POINT('',(3.64653900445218,27.5,-0.134352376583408));
#550=CARTESIAN_POINT('',(5.28317631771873,27.5,-0.281033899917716));
#551=CARTESIAN_POINT('',(6.24308439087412,27.5,-0.395253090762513));
#552=CARTESIAN_POINT('',(8.15543073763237,27.5,-0.674849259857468));
#553=CARTESIAN_POINT('',(9.10786788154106,27.5,-0.840233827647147));
#554=CARTESIAN_POINT('',(11.0057578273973,27.5,-1.21653474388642));
#555=CARTESIAN_POINT('',(11.9511910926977,27.5,-1.42754869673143));
#556=CARTESIAN_POINT('',(13.8323781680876,27.5,-1.88855596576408));
#557=CARTESIAN_POINT('',(14.7681323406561,27.5,-2.13854781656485));
#558=CARTESIAN_POINT('',(16.6519981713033,27.5,-2.6777777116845));
#559=CARTESIAN_POINT('',(17.5998839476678,27.5,-2.96779955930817));
#560=CARTESIAN_POINT('',(19.4863693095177,27.5,-3.57671795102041));
#561=CARTESIAN_POINT('',(20.4249680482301,27.5,-3.89561710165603));
#562=CARTESIAN_POINT('',(22.2883658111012,27.5,-4.55554423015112));
#563=CARTESIAN_POINT('',(23.2132128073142,27.5,-4.89643727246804));
#564=CARTESIAN_POINT('',(24.594651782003,27.5,-5.42253409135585));
#565=CARTESIAN_POINT('',(25.0540862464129,27.5,-5.60032951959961));
#566=CARTESIAN_POINT('',(25.9711665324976,27.5,-5.96043932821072));
#567=CARTESIAN_POINT('',(26.4288124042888,27.5,-6.14275358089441));
#568=CARTESIAN_POINT('',(26.8856293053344,27.5,-6.32712441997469));
#569=B_SPLINE_CURVE_WITH_KNOTS('',3,(#507,#508,#509,#510,#511,#512,#513,#514,#515,#516,#517,
#518,#519,#520,#521,#522,#523,#524,#525,#526,#527,#528,#529,#530,#531,#532,#533,#534,#535,#536,
#537,#538,#539,#540,#541,#542,#543,#544,#545,#546,#547,#548,#549,#550,#551,#552,#553,#554,#555,
#556,#557,#558,#559,#560,#561,#562,#563,#564,#565,#566,#567,#568),.UNSPECIFIED.,.F.,.F.,(4,2,2,
2,2,2,2,2,2,2,2,2,2,2,2,2,2,2,2,2,2,2,2,2,2,2,2,2,2,2,4),(0.,2.01152483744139,4.02307175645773,
6.034960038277,8.04684320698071,12.093617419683,16.1401806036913,18.1883662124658,
20.2365192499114,22.2849695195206,24.3333721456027,26.3773870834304,28.42143684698,
32.5079579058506,34.5520769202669,36.5961500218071,38.640348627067,40.6845496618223,
42.7157641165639,44.7469478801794,46.7775697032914,48.808280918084,51.7067063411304,
54.6055619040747,57.510680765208,60.4156904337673,63.3889230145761,66.3624242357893,
69.3191566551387,70.7970485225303,72.2748986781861),.UNSPECIFIED.);
#570=EDGE_CURVE('E133',#450,#117,#569,.T.);
#571=ORIENTED_EDGE('',*,*,#570,.T.);
#572=CARTESIAN_POINT('',(15.8771324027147,27.5,-2.45620093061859));
#573=VERTEX_POINT('',#572);
#574=EDGE_CURVE('E172',#117,#573,#569,.T.);
#575=ORIENTED_EDGE('',*,*,#574,.T.);
#576=DIRECTION('',(0.,0.,1.));
#577=VECTOR('',#576,1.);
#578=CARTESIAN_POINT('',(15.8771324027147,27.5,-23.52));
#579=LINE('',#578,#577);
#580=CARTESIAN_POINT('',(15.8771324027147,27.5,-21.0637990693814));
#581=VERTEX_POINT('',#580);
#582=EDGE_CURVE('E292',#581,#573,#579,.T.);
#583=ORIENTED_EDGE('',*,*,#582,.F.);
#584=CARTESIAN_POINT('',(-42.108494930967,27.5,-10.3605156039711));
#585=CARTESIAN_POINT('',(-41.5048149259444,27.5,-10.6523227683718));
#586=CARTESIAN_POINT('',(-40.9004047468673,27.5,-10.9426241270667));
#587=CARTESIAN_POINT('',(-39.6899708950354,27.5,-11.5198596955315));
#588=CARTESIAN_POINT('',(-39.0839472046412,27.5,-11.8067938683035));
#589=CARTESIAN_POINT('',(-37.8700434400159,27.5,-12.3769814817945));
#590=CARTESIAN_POINT('',(-37.2621630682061,27.5,-12.6602342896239));
#591=CARTESIAN_POINT('',(-36.0444843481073,27.5,-13.2225807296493));
#592=CARTESIAN_POINT('',(-35.4346860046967,27.5,-13.5016743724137));
#593=CARTESIAN_POINT('',(-33.5951504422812,27.5,-14.3351881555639));
#594=CARTESIAN_POINT('',(-32.3622101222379,27.5,-14.8825698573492));
#595=CARTESIAN_POINT('',(-29.8861914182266,27.5,-15.9538541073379));
#596=CARTESIAN_POINT('',(-28.6431135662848,27.5,-16.4777578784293));
#597=CARTESIAN_POINT('',(-26.761690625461,27.5,-17.2443433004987));
#598=CARTESIAN_POINT('',(-26.1278670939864,27.5,-17.4981337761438));
#599=CARTESIAN_POINT('',(-24.856813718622,27.5,-17.997025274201));
#600=CARTESIAN_POINT('',(-24.2195839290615,27.5,-18.2421264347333));
#601=CARTESIAN_POINT('',(-22.9413245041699,27.5,-18.7225185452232));
#602=CARTESIAN_POINT('',(-22.3002943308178,27.5,-18.9578080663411));
#603=CARTESIAN_POINT('',(-21.0142476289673,27.5,-19.4171975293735));
#604=CARTESIAN_POINT('',(-20.3692311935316,27.5,-19.6412977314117));
#605=CARTESIAN_POINT('',(-19.0762913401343,27.5,-20.076336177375));
#606=CARTESIAN_POINT('',(-18.4283771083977,27.5,-20.2873015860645));
#607=CARTESIAN_POINT('',(-17.1280636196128,27.5,-20.694881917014));
#608=CARTESIAN_POINT('',(-16.4756642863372,27.5,-20.8914965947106));
#609=CARTESIAN_POINT('',(-14.5117448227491,27.5,-21.4569304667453));
#610=CARTESIAN_POINT('',(-13.1930050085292,27.5,-21.8015100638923));
#611=CARTESIAN_POINT('',(-11.2007577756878,27.5,-22.2571656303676));
#612=CARTESIAN_POINT('',(-10.5341776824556,27.5,-22.3988718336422));
#613=CARTESIAN_POINT('',(-9.19657522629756,27.5,-22.6596423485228));
#614=CARTESIAN_POINT('',(-8.52555296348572,27.5,-22.778707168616));
#615=CARTESIAN_POINT('',(-7.17952384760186,27.5,-22.9920839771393));
#616=CARTESIAN_POINT('',(-6.50451675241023,27.5,-23.0863944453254));
#617=CARTESIAN_POINT('',(-5.15128946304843,27.5,-23.2483683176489));
#618=CARTESIAN_POINT('',(-4.4730692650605,27.5,-23.3160316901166));
#619=CARTESIAN_POINT('',(-3.1187108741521,27.5,-23.4228897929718));
#620=CARTESIAN_POINT('',(-2.44258682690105,27.5,-23.4622626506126));
#621=CARTESIAN_POINT('',(-1.08928096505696,27.5,-23.5123327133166));
#622=CARTESIAN_POINT('',(-0.412099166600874,27.5,-23.5230303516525));
#623=CARTESIAN_POINT('',(0.941918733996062,27.5,-23.5154963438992));
#624=CARTESIAN_POINT('',(1.61875487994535,27.5,-23.4972727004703));
#625=CARTESIAN_POINT('',(2.97106504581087,27.5,-23.4323489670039));
#626=CARTESIAN_POINT('',(3.64653900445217,27.5,-23.3856476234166));
#627=CARTESIAN_POINT('',(5.28317631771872,27.5,-23.2389661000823));
#628=CARTESIAN_POINT('',(6.2430843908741,27.5,-23.1247469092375));
#629=CARTESIAN_POINT('',(8.15543073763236,27.5,-22.8451507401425));
#630=CARTESIAN_POINT('',(9.10786788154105,27.5,-22.6797661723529));
#631=CARTESIAN_POINT('',(11.0057578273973,27.5,-22.3034652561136));
#632=CARTESIAN_POINT('',(11.9511910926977,27.5,-22.0924513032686));
#633=CARTESIAN_POINT('',(13.8323781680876,27.5,-21.6314440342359));
#634=CARTESIAN_POINT('',(14.7681323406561,27.5,-21.3814521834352));
#635=CARTESIAN_POINT('',(16.6519981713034,27.5,-20.8422222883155));
#636=CARTESIAN_POINT('',(17.5998839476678,27.5,-20.5522004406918));
#637=CARTESIAN_POINT('',(19.4863693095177,27.5,-19.9432820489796));
#638=CARTESIAN_POINT('',(20.4249680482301,27.5,-19.624382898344));
#639=CARTESIAN_POINT('',(22.2883658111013,27.5,-18.9644557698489));
#640=CARTESIAN_POINT('',(23.2132128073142,27.5,-18.623562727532));
#641=CARTESIAN_POINT('',(24.594651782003,27.5,-18.0974659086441));
#642=CARTESIAN_POINT('',(25.0540862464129,27.5,-17.9196704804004));
#643=CARTESIAN_POINT('',(25.9711665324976,27.5,-17.5595606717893));
#644=CARTESIAN_POINT('',(26.4288124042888,27.5,-17.3772464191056));
#645=CARTESIAN_POINT('',(26.8856293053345,27.5,-17.1928755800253));
#646=B_SPLINE_CURVE_WITH_KNOTS('',3,(#584,#585,#586,#587,#588,#589,#590,#591,#592,#593,#594,
#595,#596,#597,#598,#599,#600,#601,#602,#603,#604,#605,#606,#607,#608,#609,#610,#611,#612,#613,
#614,#615,#616,#617,#618,#619,#620,#621,#622,#623,#624,#625,#626,#627,#628,#629,#630,#631,#632,
#633,#634,#635,#636,#637,#638,#639,#640,#641,#642,#643,#644,#645),.UNSPECIFIED.,.F.,.F.,(4,2,2,
2,2,2,2,2,2,2,2,2,2,2,2,2,2,2,2,2,2,2,2,2,2,2,2,2,2,2,4),(0.,2.01152483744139,4.02307175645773,
6.03496003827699,8.04684320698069,12.0936174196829,16.1401806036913,18.1883662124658,
20.2365192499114,22.2849695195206,24.3333721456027,26.3773870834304,28.42143684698,
32.5079579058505,34.5520769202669,36.596150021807,38.640348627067,40.6845496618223,
42.7157641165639,44.7469478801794,46.7775697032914,48.808280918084,51.7067063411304,
54.6055619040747,57.510680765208,60.4156904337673,63.3889230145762,66.3624242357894,
69.3191566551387,70.7970485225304,72.2748986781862),.UNSPECIFIED.);
#647=EDGE_CURVE('E254',#581,#32,#646,.F.);
#648=ORIENTED_EDGE('',*,*,#647,.T.);
#649=EDGE_CURVE('E347',#32,#458,#646,.F.);
#650=ORIENTED_EDGE('',*,*,#649,.T.);
#651=EDGE_LOOP('',(#506,#571,#575,#583,#648,#650));
#652=FACE_BOUND('',#651,.T.);
#653=ADVANCED_FACE('F224',(#652),#505,.T.);
#654=CARTESIAN_POINT('',(31.7542648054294,0.,-23.52));
#655=DIRECTION('',(0.866025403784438,0.5,0.));
#656=DIRECTION('',(-0.5,0.866025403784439,0.));
#657=AXIS2_PLACEMENT_3D('',#654,#655,#656);
#658=PLANE('',#657);
#659=ORIENTED_EDGE('',*,*,#582,.T.);
#660=CARTESIAN_POINT('',(15.8770169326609,27.5002,-2.45626759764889));
#661=CARTESIAN_POINT('',(16.2259892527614,26.8957622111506,-2.25480335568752));
#662=CARTESIAN_POINT('',(16.5763227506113,26.2889667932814,-2.06248134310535));
#663=CARTESIAN_POINT('',(17.2797989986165,25.0705101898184,-1.69866297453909));
#664=CARTESIAN_POINT('',(17.6329426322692,24.4588474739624,-1.52717346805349));
#665=CARTESIAN_POINT('',(18.3427291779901,23.229461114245,-1.20732190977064));
#666=CARTESIAN_POINT('',(18.6993783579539,22.6117266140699,-1.05901508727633));
#667=CARTESIAN_POINT('',(19.4151397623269,21.371991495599,-0.788723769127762));
#668=CARTESIAN_POINT('',(19.7742517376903,20.7499913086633,-0.666736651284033));
#669=CARTESIAN_POINT('',(20.4857595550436,19.5176236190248,-0.45426290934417));
#670=CARTESIAN_POINT('',(20.8381026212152,18.907347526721,-0.363073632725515));
#671=CARTESIAN_POINT('',(21.5444032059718,17.683999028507,-0.210170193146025));
#672=CARTESIAN_POINT('',(21.8983607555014,17.0709265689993,-0.14845659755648));
#673=CARTESIAN_POINT('',(22.6068704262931,15.8437518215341,-0.0560627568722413));
#674=CARTESIAN_POINT('',(22.9614213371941,15.2296516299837,-0.0253456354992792));
#675=CARTESIAN_POINT('',(23.6708503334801,14.0008845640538,0.00439469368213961));
#676=CARTESIAN_POINT('',(24.025728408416,13.3862177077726,0.00341888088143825));
#677=CARTESIAN_POINT('',(24.6891773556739,12.2370904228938,-0.0280129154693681));
#678=CARTESIAN_POINT('',(24.9977954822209,11.7025481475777,-0.054636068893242));
#679=CARTESIAN_POINT('',(25.6142949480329,10.6347397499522,-0.131346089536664));
#680=CARTESIAN_POINT('',(25.9221762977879,10.1014736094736,-0.18143262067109));
#681=CARTESIAN_POINT('',(26.5370884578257,9.03641450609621,-0.304201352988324));
#682=CARTESIAN_POINT('',(26.8441182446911,8.50462331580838,-0.376903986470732));
#683=CARTESIAN_POINT('',(27.4567077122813,7.44358723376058,-0.543618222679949));
#684=CARTESIAN_POINT('',(27.7622673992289,6.9143423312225,-0.637629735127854));
#685=CARTESIAN_POINT('',(28.6898814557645,5.3076676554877,-0.954040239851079));
#686=CARTESIAN_POINT('',(29.3093003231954,4.23480270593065,-1.20800596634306));
#687=CARTESIAN_POINT('',(30.2315881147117,2.63735339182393,-1.64037055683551));
#688=CARTESIAN_POINT('',(30.5376130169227,2.10730271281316,-1.79290583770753));
#689=CARTESIAN_POINT('',(31.1475461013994,1.05086762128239,-2.11341869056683));
#690=CARTESIAN_POINT('',(31.4514548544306,0.52448222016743,-2.28139191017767));
#691=CARTESIAN_POINT('',(31.7543802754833,-0.000199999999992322,-2.45626759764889));
#692=B_SPLINE_CURVE_WITH_KNOTS('',3,(#660,#661,#662,#663,#664,#665,#666,#667,#668,#669,#670,
#671,#672,#673,#674,#675,#676,#677,#678,#679,#680,#681,#682,#683,#684,#685,#686,#687,#688,#689,
#690,#691),.UNSPECIFIED.,.F.,.F.,(4,2,2,2,2,2,2,2,2,2,2,2,2,2,2,4),(0.,2.17937596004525,
4.35946654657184,6.54467421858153,8.72966408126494,10.8607692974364,12.9919155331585,
15.120523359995,17.2490654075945,19.1020483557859,20.9550047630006,22.8096400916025,
24.6642675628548,28.4552152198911,30.3473870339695,32.2390270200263),.UNSPECIFIED.);
#693=EDGE_CURVE('E218',#573,#113,#692,.T.);
#694=ORIENTED_EDGE('',*,*,#693,.T.);
#695=CARTESIAN_POINT('',(31.7542648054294,0.,-2.45620093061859));
#696=VERTEX_POINT('',#695);
#697=EDGE_CURVE('E210',#113,#696,#692,.T.);
#698=ORIENTED_EDGE('',*,*,#697,.T.);
#699=DIRECTION('',(0.,0.,1.));
#700=VECTOR('',#699,1.);
#701=CARTESIAN_POINT('',(31.7542648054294,0.,-23.52));
#702=LINE('',#701,#700);
#703=CARTESIAN_POINT('',(31.7542648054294,0.,-21.0637990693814));
#704=VERTEX_POINT('',#703);
#705=EDGE_CURVE('E288',#704,#696,#702,.T.);
#706=ORIENTED_EDGE('',*,*,#705,.F.);
#707=CARTESIAN_POINT('',(31.7543802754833,-0.000199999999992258,-21.0637324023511));
#708=CARTESIAN_POINT('',(31.4054079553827,0.604237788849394,-21.2651966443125));
#709=CARTESIAN_POINT('',(31.0550744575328,1.21103320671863,-21.4575186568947));
#710=CARTESIAN_POINT('',(30.3515982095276,2.42948981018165,-21.8213370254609));
#711=CARTESIAN_POINT('',(29.9984545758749,3.04115252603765,-21.9928265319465));
#712=CARTESIAN_POINT('',(29.288668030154,4.27053888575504,-22.3126780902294));
#713=CARTESIAN_POINT('',(28.9320188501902,4.88827338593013,-22.4609849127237));
#714=CARTESIAN_POINT('',(28.2162574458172,6.12800850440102,-22.7312762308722));
#715=CARTESIAN_POINT('',(27.8571454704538,6.75000869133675,-22.853263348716));
#716=CARTESIAN_POINT('',(27.1456376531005,7.98237638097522,-23.0657370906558));
#717=CARTESIAN_POINT('',(26.7932945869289,8.59265247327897,-23.1569263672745));
#718=CARTESIAN_POINT('',(26.0869940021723,9.81600097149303,-23.309829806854));
#719=CARTESIAN_POINT('',(25.7330364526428,10.4290734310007,-23.3715434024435));
#720=CARTESIAN_POINT('',(25.024526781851,11.6562481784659,-23.4639372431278));
#721=CARTESIAN_POINT('',(24.66997587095,12.2703483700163,-23.4946543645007));
#722=CARTESIAN_POINT('',(23.960546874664,13.4991154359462,-23.5243946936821));
#723=CARTESIAN_POINT('',(23.6056687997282,14.1137822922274,-23.5234188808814));
#724=CARTESIAN_POINT('',(22.9422198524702,15.2629095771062,-23.4919870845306));
#725=CARTESIAN_POINT('',(22.6336017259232,15.7974518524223,-23.4653639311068));
#726=CARTESIAN_POINT('',(22.0171022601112,16.8652602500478,-23.3886539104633));
#727=CARTESIAN_POINT('',(21.7092209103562,17.3985263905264,-23.3385673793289));
#728=CARTESIAN_POINT('',(21.0943087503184,18.4635854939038,-23.2157986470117));
#729=CARTESIAN_POINT('',(20.787278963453,18.9953766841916,-23.1430960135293));
#730=CARTESIAN_POINT('',(20.1746894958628,20.0564127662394,-22.9763817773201));
#731=CARTESIAN_POINT('',(19.8691298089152,20.5856576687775,-22.8823702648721));
#732=CARTESIAN_POINT('',(18.9415157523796,22.1923323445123,-22.5659597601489));
#733=CARTESIAN_POINT('',(18.3220968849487,23.2651972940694,-22.3119940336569));
#734=CARTESIAN_POINT('',(17.3998090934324,24.8626466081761,-21.8796294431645));
#735=CARTESIAN_POINT('',(17.0937841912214,25.3926972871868,-21.7270941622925));
#736=CARTESIAN_POINT('',(16.4838511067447,26.4491323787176,-21.4065813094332));
#737=CARTESIAN_POINT('',(16.1799423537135,26.9755177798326,-21.2386080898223));
#738=CARTESIAN_POINT('',(15.8770169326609,27.5002,-21.0637324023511));
#739=B_SPLINE_CURVE_WITH_KNOTS('',3,(#707,#708,#709,#710,#711,#712,#713,#714,#715,#716,#717,
#718,#719,#720,#721,#722,#723,#724,#725,#726,#727,#728,#729,#730,#731,#732,#733,#734,#735,#736,
#737,#738),.UNSPECIFIED.,.F.,.F.,(4,2,2,2,2,2,2,2,2,2,2,2,2,2,2,4),(0.,2.17937596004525,
4.35946654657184,6.54467421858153,8.72966408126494,10.8607692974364,12.9919155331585,
15.120523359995,17.2490654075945,19.1020483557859,20.9550047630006,22.8096400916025,
24.6642675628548,28.4552152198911,30.3473870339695,32.2390270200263),.UNSPECIFIED.);
#740=EDGE_CURVE('E230',#704,#30,#739,.T.);
#741=ORIENTED_EDGE('',*,*,#740,.T.);
#742=EDGE_CURVE('E240',#30,#581,#739,.T.);
#743=ORIENTED_EDGE('',*,*,#742,.T.);
#744=EDGE_LOOP('',(#659,#694,#698,#706,#741,#743));
#745=FACE_BOUND('',#744,.T.);
#746=ADVANCED_FACE('F220',(#745),#658,.T.);
#747=CARTESIAN_POINT('',(15.8771324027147,-27.5,-23.52));
#748=DIRECTION('',(0.866025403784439,-0.5,0.));
#749=DIRECTION('',(0.5,0.866025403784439,0.));
#750=AXIS2_PLACEMENT_3D('',#747,#748,#749);
#751=PLANE('',#750);
#752=ORIENTED_EDGE('',*,*,#705,.T.);
#753=CARTESIAN_POINT('',(31.7543802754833,0.000200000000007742,-2.45626759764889));
#754=CARTESIAN_POINT('',(31.4054079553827,-0.60423778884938,-2.25480335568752));
#755=CARTESIAN_POINT('',(31.0550744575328,-1.21103320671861,-2.06248134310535));
#756=CARTESIAN_POINT('',(30.3515982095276,-2.42948981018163,-1.69866297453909));
#757=CARTESIAN_POINT('',(29.9984545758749,-3.04115252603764,-1.52717346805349));
#758=CARTESIAN_POINT('',(29.288668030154,-4.27053888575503,-1.20732190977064));
#759=CARTESIAN_POINT('',(28.9320188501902,-4.88827338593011,-1.05901508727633));
#760=CARTESIAN_POINT('',(28.2162574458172,-6.128008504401,-0.788723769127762));
#761=CARTESIAN_POINT('',(27.8571454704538,-6.75000869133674,-0.666736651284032));
#762=CARTESIAN_POINT('',(27.1456376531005,-7.9823763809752,-0.454262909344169));
#763=CARTESIAN_POINT('',(26.7932945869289,-8.59265247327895,-0.363073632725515));
#764=CARTESIAN_POINT('',(26.0869940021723,-9.81600097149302,-0.210170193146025));
#765=CARTESIAN_POINT('',(25.7330364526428,-10.4290734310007,-0.148456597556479));
#766=CARTESIAN_POINT('',(25.024526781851,-11.6562481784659,-0.0560627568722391));
#767=CARTESIAN_POINT('',(24.66997587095,-12.2703483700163,-0.025345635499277));
#768=CARTESIAN_POINT('',(23.960546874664,-13.4991154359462,0.00439469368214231));
#769=CARTESIAN_POINT('',(23.6056687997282,-14.1137822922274,0.00341888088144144));
#770=CARTESIAN_POINT('',(22.9422198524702,-15.2629095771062,-0.0280129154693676));
#771=CARTESIAN_POINT('',(22.6336017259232,-15.7974518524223,-0.0546360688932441));
#772=CARTESIAN_POINT('',(22.0171022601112,-16.8652602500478,-0.131346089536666));
#773=CARTESIAN_POINT('',(21.7092209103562,-17.3985263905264,-0.181432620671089));
#774=CARTESIAN_POINT('',(21.0943087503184,-18.4635854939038,-0.30420135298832));
#775=CARTESIAN_POINT('',(20.787278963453,-18.9953766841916,-0.376903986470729));
#776=CARTESIAN_POINT('',(20.1746894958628,-20.0564127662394,-0.543618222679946));
#777=CARTESIAN_POINT('',(19.8691298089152,-20.5856576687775,-0.637629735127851));
#778=CARTESIAN_POINT('',(18.9415157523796,-22.1923323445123,-0.954040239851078));
#779=CARTESIAN_POINT('',(18.3220968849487,-23.2651972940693,-1.20800596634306));
#780=CARTESIAN_POINT('',(17.3998090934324,-24.8626466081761,-1.64037055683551));
#781=CARTESIAN_POINT('',(17.0937841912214,-25.3926972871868,-1.79290583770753));
#782=CARTESIAN_POINT('',(16.4838511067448,-26.4491323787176,-2.11341869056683));
#783=CARTESIAN_POINT('',(16.1799423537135,-26.9755177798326,-2.28139191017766));
#784=CARTESIAN_POINT('',(15.8770169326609,-27.5002,-2.45626759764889));
#785=B_SPLINE_CURVE_WITH_KNOTS('',3,(#753,#754,#755,#756,#757,#758,#759,#760,#761,#762,#763,
#764,#765,#766,#767,#768,#769,#770,#771,#772,#773,#774,#775,#776,#777,#778,#779,#780,#781,#782,
#783,#784),.UNSPECIFIED.,.F.,.F.,(4,2,2,2,2,2,2,2,2,2,2,2,2,2,2,4),(0.,2.17937596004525,
4.35946654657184,6.54467421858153,8.72966408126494,10.8607692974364,12.9919155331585,
15.120523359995,17.2490654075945,19.1020483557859,20.9550047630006,22.8096400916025,
24.6642675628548,28.4552152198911,30.3473870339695,32.2390270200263),.UNSPECIFIED.);
#786=EDGE_CURVE('E219',#696,#111,#785,.T.);
#787=ORIENTED_EDGE('',*,*,#786,.T.);
#788=EDGE_CURVE('E155',#111,#165,#785,.T.);
#789=ORIENTED_EDGE('',*,*,#788,.T.);
#790=ORIENTED_EDGE('',*,*,#166,.F.);
#791=CARTESIAN_POINT('',(15.8770169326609,-27.5002,-21.0637324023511));
#792=CARTESIAN_POINT('',(16.2259892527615,-26.8957622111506,-21.2651966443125));
#793=CARTESIAN_POINT('',(16.5763227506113,-26.2889667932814,-21.4575186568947));
#794=CARTESIAN_POINT('',(17.2797989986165,-25.0705101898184,-21.8213370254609));
#795=CARTESIAN_POINT('',(17.6329426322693,-24.4588474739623,-21.9928265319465));
#796=CARTESIAN_POINT('',(18.3427291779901,-23.229461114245,-22.3126780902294));
#797=CARTESIAN_POINT('',(18.6993783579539,-22.6117266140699,-22.4609849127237));
#798=CARTESIAN_POINT('',(19.4151397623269,-21.371991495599,-22.7312762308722));
#799=CARTESIAN_POINT('',(19.7742517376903,-20.7499913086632,-22.853263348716));
#800=CARTESIAN_POINT('',(20.4857595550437,-19.5176236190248,-23.0657370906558));
#801=CARTESIAN_POINT('',(20.8381026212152,-18.907347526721,-23.1569263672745));
#802=CARTESIAN_POINT('',(21.5444032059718,-17.683999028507,-23.309829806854));
#803=CARTESIAN_POINT('',(21.8983607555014,-17.0709265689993,-23.3715434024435));
#804=CARTESIAN_POINT('',(22.6068704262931,-15.8437518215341,-23.4639372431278));
#805=CARTESIAN_POINT('',(22.9614213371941,-15.2296516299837,-23.4946543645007));
#806=CARTESIAN_POINT('',(23.6708503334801,-14.0008845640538,-23.5243946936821));
#807=CARTESIAN_POINT('',(24.025728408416,-13.3862177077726,-23.5234188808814));
#808=CARTESIAN_POINT('',(24.6891773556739,-12.2370904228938,-23.4919870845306));
#809=CARTESIAN_POINT('',(24.9977954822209,-11.7025481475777,-23.4653639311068));
#810=CARTESIAN_POINT('',(25.6142949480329,-10.6347397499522,-23.3886539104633));
#811=CARTESIAN_POINT('',(25.9221762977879,-10.1014736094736,-23.3385673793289));
#812=CARTESIAN_POINT('',(26.5370884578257,-9.0364145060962,-23.2157986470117));
#813=CARTESIAN_POINT('',(26.8441182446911,-8.50462331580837,-23.1430960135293));
#814=CARTESIAN_POINT('',(27.4567077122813,-7.44358723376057,-22.9763817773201));
#815=CARTESIAN_POINT('',(27.7622673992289,-6.91434233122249,-22.8823702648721));
#816=CARTESIAN_POINT('',(28.6898814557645,-5.30766765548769,-22.5659597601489));
#817=CARTESIAN_POINT('',(29.3093003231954,-4.23480270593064,-22.3119940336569));
#818=CARTESIAN_POINT('',(30.2315881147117,-2.63735339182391,-21.8796294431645));
#819=CARTESIAN_POINT('',(30.5376130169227,-2.10730271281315,-21.7270941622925));
#820=CARTESIAN_POINT('',(31.1475461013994,-1.05086762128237,-21.4065813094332));
#821=CARTESIAN_POINT('',(31.4514548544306,-0.524482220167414,-21.2386080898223));
#822=CARTESIAN_POINT('',(31.7543802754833,0.000200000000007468,-21.0637324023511));
#823=B_SPLINE_CURVE_WITH_KNOTS('',3,(#791,#792,#793,#794,#795,#796,#797,#798,#799,#800,#801,
#802,#803,#804,#805,#806,#807,#808,#809,#810,#811,#812,#813,#814,#815,#816,#817,#818,#819,#820,
#821,#822),.UNSPECIFIED.,.F.,.F.,(4,2,2,2,2,2,2,2,2,2,2,2,2,2,2,4),(0.,2.17937596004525,
4.35946654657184,6.54467421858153,8.72966408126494,10.8607692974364,12.9919155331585,
15.120523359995,17.2490654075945,19.1020483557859,20.9550047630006,22.8096400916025,
24.6642675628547,28.4552152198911,30.3473870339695,32.2390270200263),.UNSPECIFIED.);
#824=EDGE_CURVE('E239',#163,#36,#823,.T.);
#825=ORIENTED_EDGE('',*,*,#824,.T.);
#826=EDGE_CURVE('E241',#36,#704,#823,.T.);
#827=ORIENTED_EDGE('',*,*,#826,.T.);
#828=EDGE_LOOP('',(#752,#787,#789,#790,#825,#827));
#829=FACE_BOUND('',#828,.T.);
#830=ADVANCED_FACE('F223',(#829),#751,.T.);
#831=CARTESIAN_POINT('',(0.,0.,-23.52));
#832=DIRECTION('',(0.,0.,1.));
#833=DIRECTION('',(1.,0.,0.));
#834=AXIS2_PLACEMENT_3D('',#831,#832,#833);
#835=CONICAL_SURFACE('',#834,27.5,1.0471975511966);
#836=ORIENTED_EDGE('',*,*,#826,.F.);
#837=ORIENTED_EDGE('',*,*,#37,.T.);
#838=ORIENTED_EDGE('',*,*,#740,.F.);
#839=EDGE_LOOP('',(#836,#837,#838));
#840=FACE_BOUND('',#839,.T.);
#841=ADVANCED_FACE('F197',(#840),#835,.T.);
#842=ORIENTED_EDGE('',*,*,#41,.T.);
#843=ORIENTED_EDGE('',*,*,#824,.F.);
#844=ORIENTED_EDGE('',*,*,#310,.F.);
#845=EDGE_LOOP('',(#842,#843,#844));
#846=FACE_BOUND('',#845,.T.);
#847=ADVANCED_FACE('F383',(#846),#835,.T.);
#848=ORIENTED_EDGE('',*,*,#45,.T.);
#849=ORIENTED_EDGE('',*,*,#308,.F.);
#850=ORIENTED_EDGE('',*,*,#403,.F.);
#851=EDGE_LOOP('',(#848,#849,#850));
#852=FACE_BOUND('',#851,.T.);
#853=ADVANCED_FACE('F394',(#852),#835,.T.);
#854=ORIENTED_EDGE('',*,*,#49,.T.);
#855=ORIENTED_EDGE('',*,*,#401,.F.);
#856=ORIENTED_EDGE('',*,*,#496,.F.);
#857=EDGE_LOOP('',(#854,#855,#856));
#858=FACE_BOUND('',#857,.T.);
#859=ADVANCED_FACE('F399',(#858),#835,.T.);
#860=ORIENTED_EDGE('',*,*,#649,.F.);
#861=ORIENTED_EDGE('',*,*,#56,.F.);
#862=ORIENTED_EDGE('',*,*,#494,.F.);
#863=EDGE_LOOP('',(#860,#861,#862));
#864=FACE_BOUND('',#863,.T.);
#865=ADVANCED_FACE('F397',(#864),#835,.T.);
#866=ORIENTED_EDGE('',*,*,#742,.F.);
#867=ORIENTED_EDGE('',*,*,#33,.T.);
#868=ORIENTED_EDGE('',*,*,#647,.F.);
#869=EDGE_LOOP('',(#866,#867,#868));
#870=FACE_BOUND('',#869,.T.);
#871=ADVANCED_FACE('F192',(#870),#835,.T.);
#872=CARTESIAN_POINT('',(0.,0.,-2.45620093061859));
#873=DIRECTION('',(0.,0.,-1.));
#874=DIRECTION('',(-1.,0.,0.));
#875=AXIS2_PLACEMENT_3D('',#872,#873,#874);
#876=CONICAL_SURFACE('',#875,31.7542648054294,1.0471975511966);
#877=ORIENTED_EDGE('',*,*,#114,.F.);
#878=ORIENTED_EDGE('',*,*,#786,.F.);
#879=ORIENTED_EDGE('',*,*,#697,.F.);
#880=EDGE_LOOP('',(#877,#878,#879));
#881=FACE_BOUND('',#880,.T.);
#882=ADVANCED_FACE('F186',(#881),#876,.T.);
#883=ORIENTED_EDGE('',*,*,#788,.F.);
#884=ORIENTED_EDGE('',*,*,#137,.F.);
#885=ORIENTED_EDGE('',*,*,#231,.F.);
#886=EDGE_LOOP('',(#883,#884,#885));
#887=FACE_BOUND('',#886,.T.);
#888=ADVANCED_FACE('F191',(#887),#876,.T.);
#889=ORIENTED_EDGE('',*,*,#135,.F.);
#890=ORIENTED_EDGE('',*,*,#354,.F.);
#891=ORIENTED_EDGE('',*,*,#235,.F.);
#892=EDGE_LOOP('',(#889,#890,#891));
#893=FACE_BOUND('',#892,.T.);
#894=ADVANCED_FACE('F367',(#893),#876,.T.);
#895=ORIENTED_EDGE('',*,*,#131,.F.);
#896=ORIENTED_EDGE('',*,*,#447,.F.);
#897=ORIENTED_EDGE('',*,*,#358,.F.);
#898=EDGE_LOOP('',(#895,#896,#897));
#899=FACE_BOUND('',#898,.T.);
#900=ADVANCED_FACE('F143',(#899),#876,.T.);
#901=ORIENTED_EDGE('',*,*,#127,.T.);
#902=ORIENTED_EDGE('',*,*,#570,.F.);
#903=ORIENTED_EDGE('',*,*,#451,.F.);
#904=EDGE_LOOP('',(#901,#902,#903));
#905=FACE_BOUND('',#904,.T.);
#906=ADVANCED_FACE('F129',(#905),#876,.T.);
#907=ORIENTED_EDGE('',*,*,#118,.F.);
#908=ORIENTED_EDGE('',*,*,#693,.F.);
#909=ORIENTED_EDGE('',*,*,#574,.F.);
#910=EDGE_LOOP('',(#907,#908,#909));
#911=FACE_BOUND('',#910,.T.);
#912=ADVANCED_FACE('F194',(#911),#876,.T.);
#913=CARTESIAN_POINT('',(0.,0.,130.364689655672));
#914=DIRECTION('',(0.,0.,-1.));
#915=DIRECTION('',(-1.,0.,0.));
#916=AXIS2_PLACEMENT_3D('',#913,#914,#915);
#917=CYLINDRICAL_SURFACE('',#916,26.9);
#918=CARTESIAN_POINT('',(0.,0.,14.304));
#919=DIRECTION('',(0.,0.,1.));
#920=DIRECTION('',(1.,0.,0.));
#921=AXIS2_PLACEMENT_3D('',#918,#919,#920);
#922=CIRCLE('',#921,26.9);
#923=CARTESIAN_POINT('',(26.9,0.,14.304));
#924=VERTEX_POINT('',#923);
#925=EDGE_CURVE('E12',#924,#924,#922,.F.);
#926=ORIENTED_EDGE('',*,*,#925,.T.);
#927=EDGE_LOOP('',(#926));
#928=FACE_BOUND('',#927,.T.);
#929=ORIENTED_EDGE('',*,*,#148,.T.);
#930=EDGE_LOOP('',(#929));
#931=FACE_BOUND('',#930,.T.);
#932=ADVANCED_FACE('F195',(#928,#931),#917,.T.);
#933=CARTESIAN_POINT('',(47.6313972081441,-27.5,15.38));
#934=DIRECTION('',(0.,0.,1.));
#935=DIRECTION('',(1.,0.,0.));
#936=AXIS2_PLACEMENT_3D('',#933,#934,#935);
#937=PLANE('',#936);
#938=CARTESIAN_POINT('',(0.,0.,15.38));
#939=DIRECTION('',(0.,0.,1.));
#940=DIRECTION('',(1.,0.,0.));
#941=AXIS2_PLACEMENT_3D('',#938,#939,#940);
#942=CIRCLE('',#941,25.824);
#943=CARTESIAN_POINT('',(25.824,0.,15.38));
#944=VERTEX_POINT('',#943);
#945=EDGE_CURVE('E45',#944,#944,#942,.T.);
#946=ORIENTED_EDGE('',*,*,#945,.T.);
#947=EDGE_LOOP('',(#946));
#948=FACE_BOUND('',#947,.T.);
#949=ORIENTED_EDGE('',*,*,#84,.F.);
#950=EDGE_LOOP('',(#949));
#951=FACE_BOUND('',#950,.T.);
#952=ADVANCED_FACE('F309',(#948,#951),#937,.T.);
#953=CARTESIAN_POINT('',(0.,0.,-22.3941669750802));
#954=DIRECTION('',(0.,0.,-1.));
#955=DIRECTION('',(-1.,0.,0.));
#956=AXIS2_PLACEMENT_3D('',#953,#954,#955);
#957=CONICAL_SURFACE('',#956,17.5,1.0471975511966);
#958=ORIENTED_EDGE('',*,*,#67,.T.);
#959=EDGE_LOOP('',(#958));
#960=FACE_BOUND('',#959,.T.);
#961=ORIENTED_EDGE('',*,*,#95,.F.);
#962=EDGE_LOOP('',(#961));
#963=FACE_BOUND('',#962,.T.);
#964=ADVANCED_FACE('F313',(#960,#963),#957,.F.);
#965=CARTESIAN_POINT('',(0.,0.,15.38));
#966=DIRECTION('',(0.,0.,-1.));
#967=DIRECTION('',(-1.,0.,0.));
#968=AXIS2_PLACEMENT_3D('',#965,#966,#967);
#969=CONICAL_SURFACE('',#968,25.824,0.785398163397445);
#970=ORIENTED_EDGE('',*,*,#925,.F.);
#971=EDGE_LOOP('',(#970));
#972=FACE_BOUND('',#971,.T.);
#973=ORIENTED_EDGE('',*,*,#945,.F.);
#974=EDGE_LOOP('',(#973));
#975=FACE_BOUND('',#974,.T.);
#976=ADVANCED_FACE('F39',(#972,#975),#969,.T.);
#977=CLOSED_SHELL('',(#71,#99,#152,#314,#407,#500,#653,#746,#830,#841,#847,#853,#859,#865,#871,
#882,#888,#894,#900,#906,#912,#932,#952,#964,#976));
#978=MANIFOLD_SOLID_BREP('B2',#977);
#979=ADVANCED_BREP_SHAPE_REPRESENTATION('',(#18,#978),#14);
#980=SHAPE_DEFINITION_REPRESENTATION(#9,#979);
ENDSEC;
END-ISO-10303-21;
